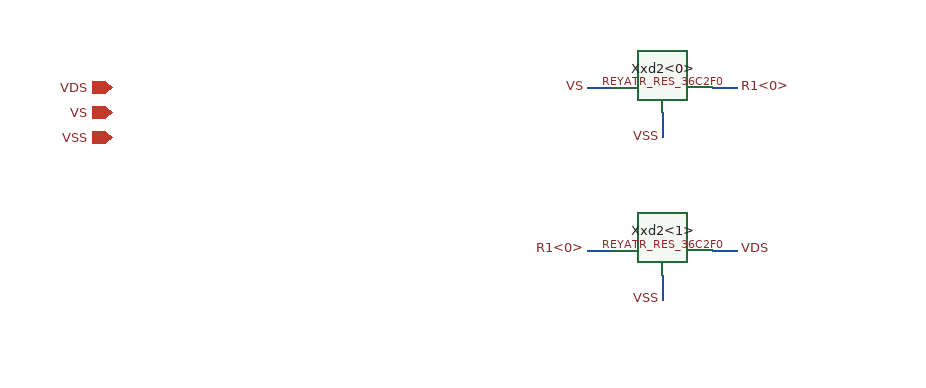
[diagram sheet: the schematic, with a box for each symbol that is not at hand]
v {xschem version=3.0.0 file_version=1.2 }
G {}
K {}
V {}
S {}
E {}
C {devices/iopin.sym} 0 0 0 0 {name=p0 lab=VDS}
C {devices/iopin.sym} 0 20 0 0 {name=p1 lab=VS}
C {devices/iopin.sym} 0 40 0 0 {name=p2 lab=VSS}
C {LELO_TEMP_SKY130A/REYATR_RES_36C2F0.sym} 400 0 0 0 {name=Xxd2<0>}
N 500.0 0.0 480.0 0.0 {lab=R1<0>}
C {devices/lab_pin.sym} 500.0 0.0 2 0 {name=l0 sig_type=std_logic lab=R1<0> }
N 380.0 0.0 400.0 0.0 {lab=VS}
C {devices/lab_pin.sym} 380.0 0.0 0 0 {name=l1 sig_type=std_logic lab=VS }
N 440.0 40.0 440.0 20.0 {lab=VSS}
C {devices/lab_pin.sym} 440.0 40.0 1 0 {name=l2 sig_type=std_logic lab=VSS }
C {LELO_TEMP_SKY130A/REYATR_RES_36C2F0.sym} 400 130.0 0 0 {name=Xxd2<1>}
N 500.0 130.0 480.0 130.0 {lab=VDS}
C {devices/lab_pin.sym} 500.0 130.0 2 0 {name=l3 sig_type=std_logic lab=VDS }
N 380.0 130.0 400.0 130.0 {lab=R1<0>}
C {devices/lab_pin.sym} 380.0 130.0 0 0 {name=l4 sig_type=std_logic lab=R1<0> }
N 440.0 170.0 440.0 150.0 {lab=VSS}
C {devices/lab_pin.sym} 440.0 170.0 1 0 {name=l5 sig_type=std_logic lab=VSS }
